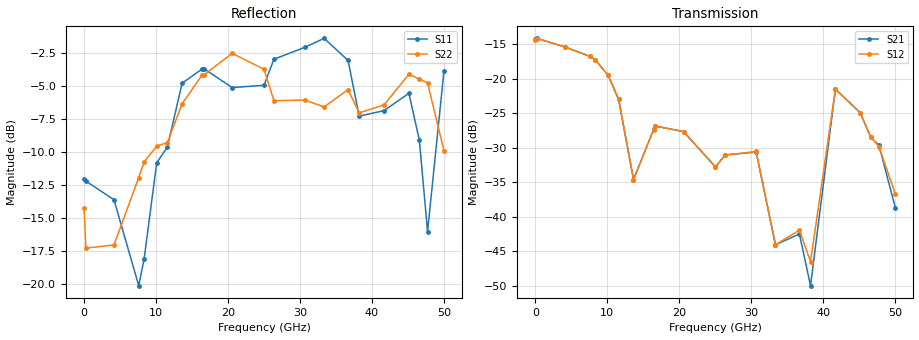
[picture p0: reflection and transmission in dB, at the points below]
!Keysight Technologies,N5245B,MY58422270,A.16.20.02
!Date: Thursday, March 05, 2026 01:01:24
!Correction: S11(C  2-Port  )
!S21(C  2-Port  )
!S12(C  2-Port  )
!S22(C  2-Port  )
!S2P File: Measurements: S11, S21, S12, S22:
# Hz S  dB  R 50
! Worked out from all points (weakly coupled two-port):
!   3201 points, 10 MHz to 50 GHz, reference 50 ohm
!   highest |S21| = -14.13 dB at 259.9 MHz (marker M1); lowest = -50.0 dB at 38.22 GHz (marker M2)
!   lowest |S11| = -20.2 dB at 7.602 GHz (marker M3), VSWR 1.22, Z = 41.1 - j1.03 ohm
!   |S11| at or under -10 dB: start of sweep to 10.39 GHz; 46.72 GHz to 48.26 GHz (1.538 GHz wide, 3.24 % of centre)
!   |S22| runs from -17.7 to -2.5 dB; largest |S21 - S12| = 0.0079
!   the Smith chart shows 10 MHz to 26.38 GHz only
!   S11 on the Smith chart (normalised r, x): 10 MHz: 1.66, -0.01; 10.1 GHz: 0.56, +0.08; 13.63 GHz: 0.97, +1.39; 16.43 GHz: 1.64, -2.11; 20.58 GHz: 0.35, -0.45; 26.38 GHz: 0.18, +0.26
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1e7  -12.07 -0.8  -14.16 5.3  -14.39 3.6  -14.28 38.5
2.5995e8  -12.23 -9.2  -14.13 -9.9  -14.18 -10.1  -17.31 -4.1
4.165419e9  -13.64 -133.0  -15.40 -171.7  -15.41 -171.7  -17.07 -121.5
7.602231e9  -20.16 -172.8  -16.75 39.7  -16.74 39.6  -11.96 -156.0
8.352081e9  -18.13 -161.6  -17.29 6.0  -17.28 6.0  -10.77 -173.4
1.010173e10  -10.84 166.8  -19.46 -72.1  -19.43 -72.2  -9.57 131.3
1.157019e10  -9.66 118.9  -22.98 -135.7  -22.96 -135.7  -9.32 60.9
1.363228e10  -4.80 56.0  -34.60 176.7  -34.66 176.9  -6.36 -44.8
1.642859e10  -3.71 -34.5  -27.32 166.9  -27.36 166.6  -4.16 -138.9
1.667854e10  -3.71 -41.9  -26.85 157.9  -26.84 157.4  -4.16 -144.2
2.058401e10  -5.13 -127.1  -27.65 34.0  -27.64 33.9  -2.54 147.8
2.5005e10  -4.96 174.4  -32.79 -66.5  -32.73 -66.6  -3.75 70.6
2.637972e10  -2.98 150.0  -31.03 -93.2  -31.07 -93.0  -6.13 40.4
3.067574e10  -2.08 78.4  -30.61 119.8  -30.53 120.0  -6.08 -55.1
3.334708e10  -1.40 35.6  -44.06 0.1  -44.06 -3.2  -6.60 -132.7
3.667454e10  -3.07 -30.9  -42.49 105.8  -41.93 100.7  -5.29 159.1
3.822111e10  -7.30 -21.8  -49.99 -139.1  -46.52 -32.1  -7.05 133.8
4.167354e10  -6.88 -55.0  -21.51 -57.0  -21.48 -57.2  -6.45 110.2
4.512598e10  -5.57 -102.1  -24.91 85.6  -24.90 85.6  -4.12 74.0
4.657881e10  -9.11 -153.0  -28.48 33.7  -28.42 33.6  -4.49 53.9
4.771921e10  -16.06 69.4  -29.61 -13.7  -29.81 -13.7  -4.77 41.6
5e10  -3.86 -72.6  -38.69 -108.3  -36.71 -136.6  -9.93 8.4
